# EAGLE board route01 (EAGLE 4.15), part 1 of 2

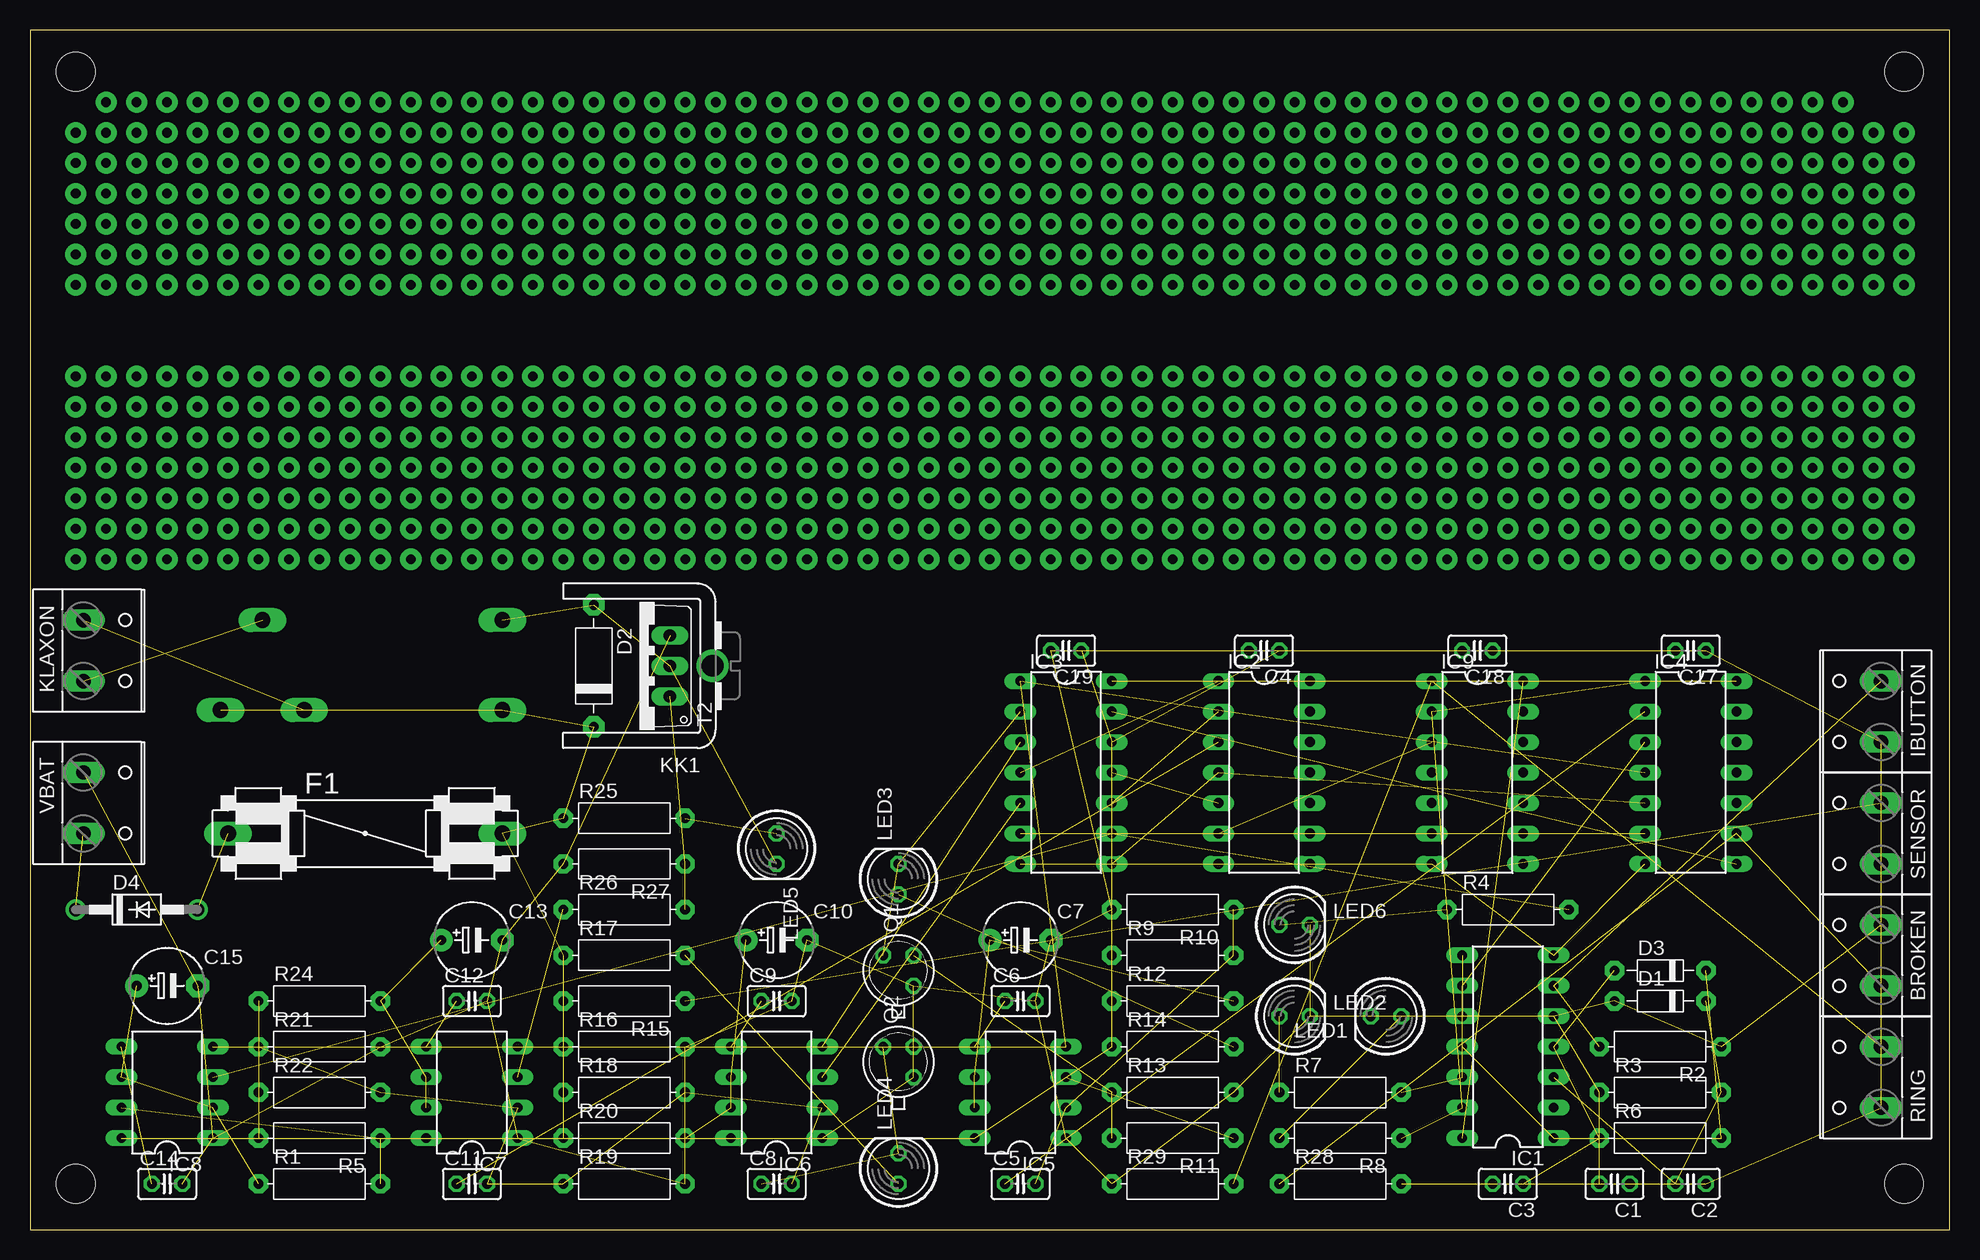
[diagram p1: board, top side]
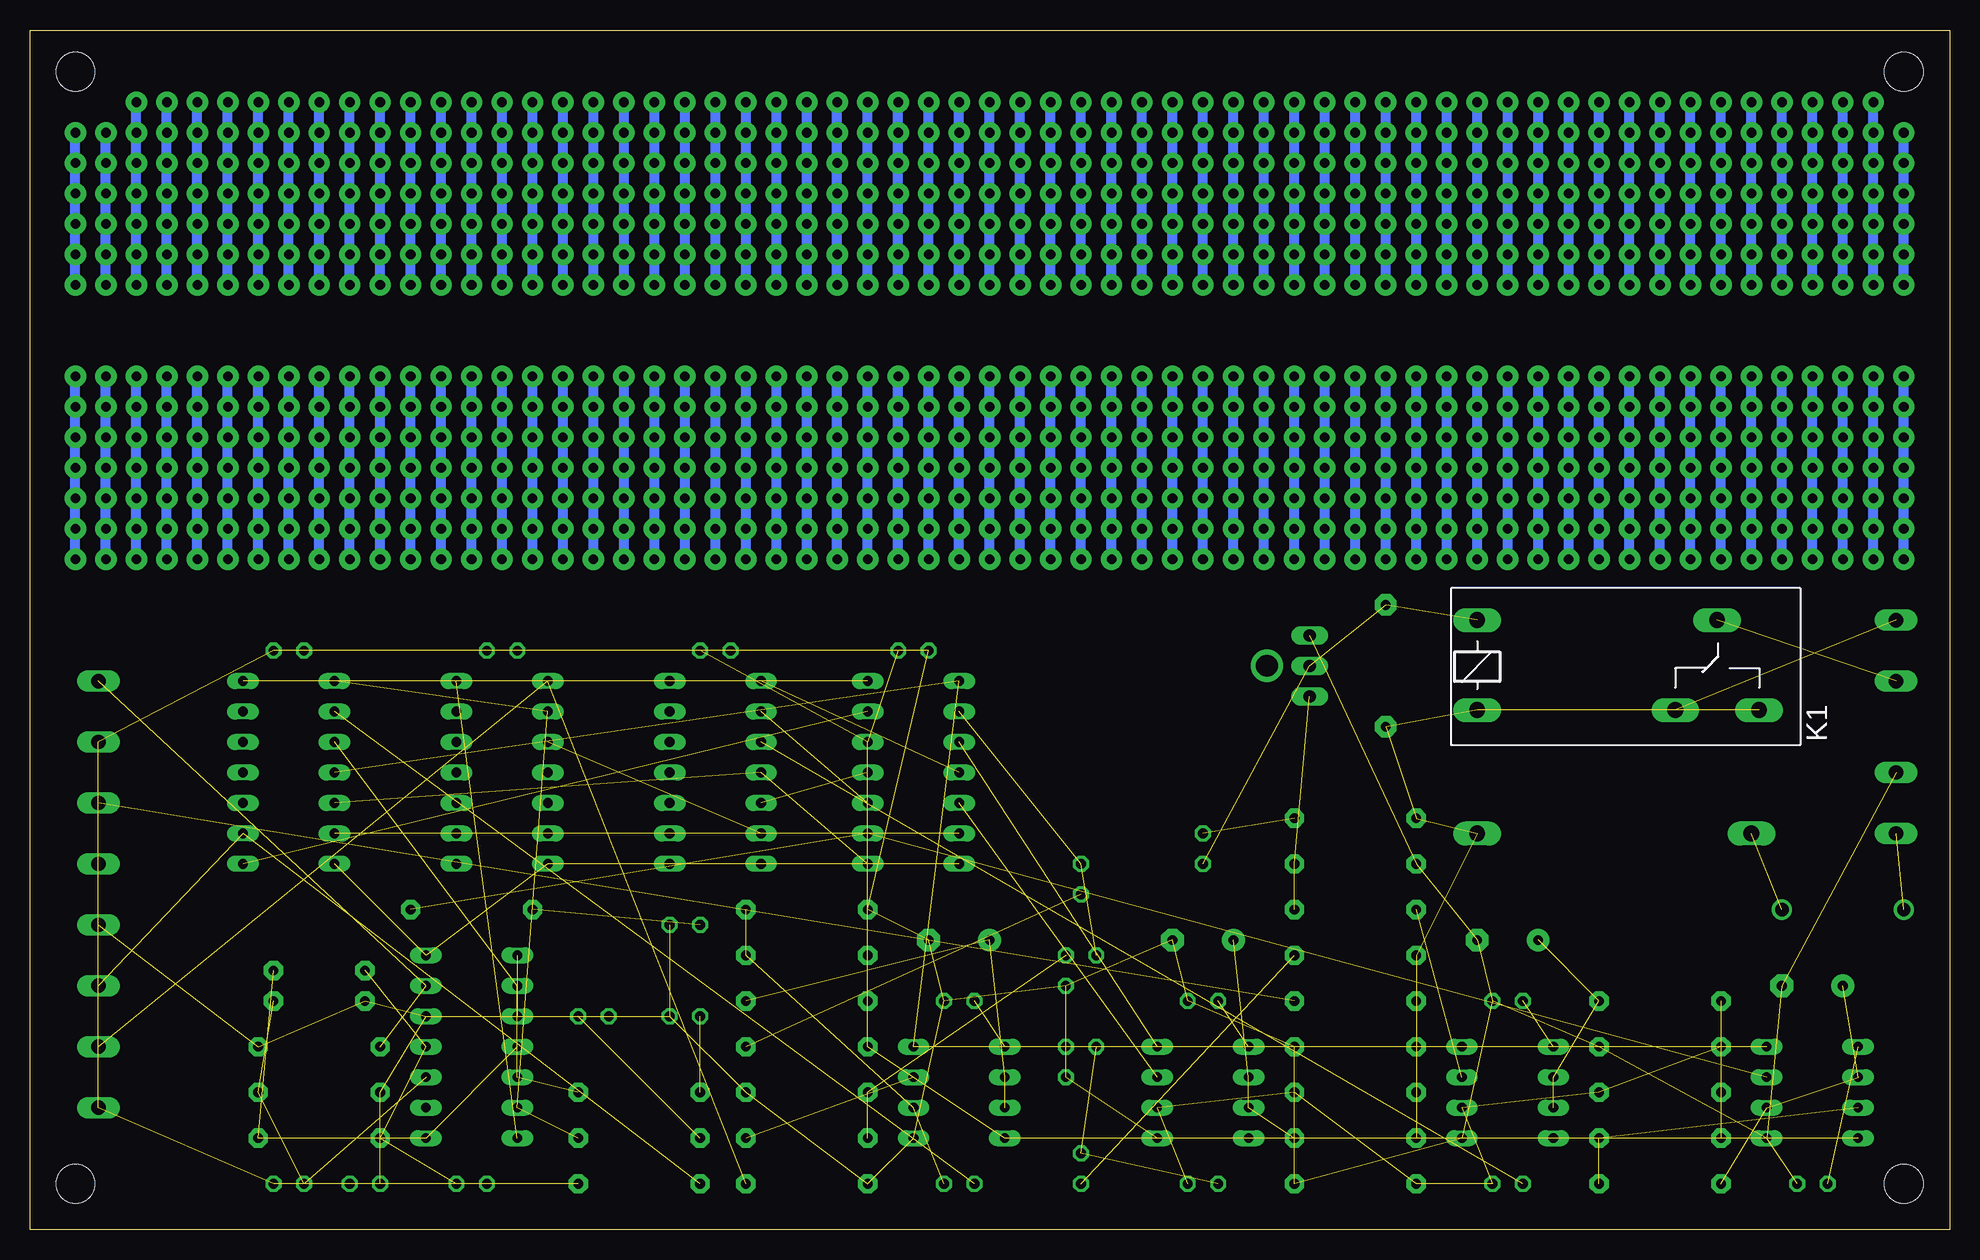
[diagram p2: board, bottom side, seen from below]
Size 160 x 100 mm. Coordinates in mm from the lower left corner, seen from the top.
Outline: 0,0 160,0 160,100 0,100 0,0
Copper layers (1*16): Top 0.035mm / dielectric 1.5mm / Bottom 0.035mm
Design rules "default": minimum track width 10mil, minimum drill 24mil, track to track 8mil, track to pad 8mil, pad to pad 8mil, via to via 8mil, smd to smd 8mil, copper to edge 40mil, drill to drill 8mil, minimum pad ring 10mil, minimum via ring 8mil, stop-mask expansion 4mil, vias tented up to drill 0mil, thermal gap 10mil
Holes 3.2 mm at 156.21,3.81 156.21,96.52 3.81,96.52 3.81,3.81

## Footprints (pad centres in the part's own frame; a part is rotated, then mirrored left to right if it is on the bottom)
W237-132 = drill 1.194 long: 1 -2.54,-0.635; 2 2.54,-0.635
C025-025X050 = drill 0.813 octagon: 1 -1.27,0; 2 1.27,0
E5-6 = drill 0.813 pad 1.905 round: + -2.54,0 | drill 0.813 pad 1.905 octagon: - 2.54,0
D-7,5 = drill 0.813 pad 1.6 octagon: 1 -3.81,0; 2 3.81,0
D-10 = drill 0.813 pad 1.778 octagon: 1 -5.08,0; 2 5.08,0
DO41-10 = drill 1.118 round: A 5.08,0; C -5.08,0
FUSE = drill 1.321 long: 1 -11.43,0; 2 11.43,0
DIL14 = drill 0.813 long: 1 -7.62,-3.81; 2 -5.08,-3.81; 3 -2.54,-3.81; 4 0,-3.81; 5 2.54,-3.81; 6 5.08,-3.81; 7 7.62,-3.81; 8 7.62,3.81; 9 5.08,3.81; 10 2.54,3.81; 11 0,3.81; 12 -2.54,3.81; 13 -5.08,3.81; 14 -7.62,3.81
DIL08 = drill 0.813 long: 1 -3.81,-3.81; 2 -1.27,-3.81; 3 1.27,-3.81; 4 3.81,-3.81; 5 3.81,3.81; 6 1.27,3.81; 7 -1.27,3.81; 8 -3.81,3.81
G2R = drill 1.321 long: 1 -2.54,-3.683; 2 -2.54,3.81; O 13.97,-3.683; P 17.45,3.81; S 20.955,-3.683
D01PA = drill 1.803 pad 2.54 round: B 0,-1.016
LED5MM = drill 0.813 octagon: A -1.27,0; K 1.27,0
TO18A = drill 0.813 octagon: B 1.27,-1.27; C 1.27,1.27; E -1.27,-1.27
R-10 = drill 0.813 pad 1.6 octagon: 1 -5.08,0; 2 5.08,0
TO220V = drill 1.016 long: 1 -2.54,-2.54; 2 0,-2.54; 3 2.54,-2.54

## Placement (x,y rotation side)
BROKEN  [W237-132]  153.67,22.86 90 top
C1  [C025-025X050]  132.08,3.81 180 top
C2  [C025-025X050]  138.43,3.81 180 top
C3  [C025-025X050]  123.19,3.81 180 top
C4  [C025-025X050]  102.87,48.26 180 top
C5  [C025-025X050]  82.55,3.81 0 top
C6  [C025-025X050]  82.55,19.05 0 top
C7  [E5-6]  82.55,24.13 0 top
C8  [C025-025X050]  62.23,3.81 0 top
C9  [C025-025X050]  62.23,19.05 0 top
C10  [E5-6]  62.23,24.13 0 top
C11  [C025-025X050]  36.83,3.81 0 top
C12  [C025-025X050]  36.83,19.05 0 top
C13  [E5-6]  36.83,24.13 0 top
C14  [C025-025X050]  11.43,3.81 0 top
C15  [E5-6]  11.43,20.32 0 top
C17  [C025-025X050]  138.43,48.26 180 top
C18  [C025-025X050]  120.65,48.26 180 top
C19  [C025-025X050]  86.36,48.26 180 top
D1  [D-7,5]  135.89,19.05 0 top
D2  [D-10]  46.99,46.99 270 top
D3  [D-7,5]  135.89,21.59 0 top
D4  1N4004  [DO41-10]  8.89,26.67 0 top
F1  [FUSE]  27.94,33.02 0 top
IBUTTON  [W237-132]  153.67,43.18 90 top
IC1  4013N  [DIL14]  123.19,15.24 90 top
IC2  4071N  [DIL14]  102.87,38.1 270 top
IC3  4081N  [DIL14]  86.36,38.1 270 top
IC4  4069N  [DIL14]  138.43,38.1 270 top
IC5  NE555N  [DIL08]  82.55,11.43 90 top
IC6  NE555N  [DIL08]  62.23,11.43 90 top
IC7  NE555N  [DIL08]  36.83,11.43 90 top
IC8  NE555N  [DIL08]  11.43,11.43 90 top
IC9  4081N  [DIL14]  120.65,38.1 270 top
K1  G2R  [G2R]  36.83,46.99 0 bottom
KK1  D01PA  [D01PA]  55.88,46.99 90 top
KLAXON  [W237-132]  5.08,48.26 270 top
LED1  [LED5MM]  113.03,17.78 180 top
LED2  [LED5MM]  105.41,17.78 0 top
LED3  [LED5MM]  72.39,29.21 90 top
LED4  [LED5MM]  72.39,5.08 90 top
LED5  [LED5MM]  62.23,31.75 270 top
LED6  [LED5MM]  105.41,25.4 0 top
Q1  2N2222  [TO18A]  72.39,21.59 90 top
Q2  2N2222  [TO18A]  72.39,13.97 90 top
R1  [R-10]  24.13,3.81 0 top
R2  [R-10]  135.89,15.24 180 top
R3  [R-10]  135.89,11.43 0 top
R4  [R-10]  123.19,26.67 0 top
R5  [R-10]  24.13,7.62 180 top
R6  [R-10]  135.89,7.62 0 top
R7  [R-10]  109.22,11.43 0 top
R8  [R-10]  109.22,7.62 180 top
R9  [R-10]  95.25,22.86 0 top
R10  [R-10]  95.25,26.67 180 top
R11  [R-10]  95.25,7.62 180 top
R12  [R-10]  95.25,19.05 0 top
R13  [R-10]  95.25,11.43 0 top
R14  [R-10]  95.25,15.24 0 top
R15  [R-10]  49.53,19.05 180 top
R16  [R-10]  49.53,15.24 0 top
R17  [R-10]  49.53,22.86 0 top
R18  [R-10]  49.53,11.43 0 top
R19  [R-10]  49.53,3.81 0 top
R20  [R-10]  49.53,7.62 0 top
R21  [R-10]  24.13,15.24 0 top
R22  [R-10]  24.13,11.43 0 top
R24  [R-10]  24.13,19.05 0 top
R25  [R-10]  49.53,34.29 0 top
R26  [R-10]  49.53,26.67 0 top
R27  [R-10]  49.53,30.48 180 top
R28  [R-10]  109.22,3.81 0 top
R29  [R-10]  95.25,3.81 0 top
RING  [W237-132]  153.67,12.7 90 top
SENSOR  [W237-132]  153.67,33.02 90 top
T2  [TO220V]  50.8,46.99 90 top
VBAT  [W237-132]  5.08,35.56 270 top

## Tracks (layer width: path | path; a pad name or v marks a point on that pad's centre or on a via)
ACTION  (1 unrouted)
ALERTE  (2 unrouted)
ARRACHEMENT  (2 unrouted)
BP_URGENCE  (2 unrouted)
CDE  (1 unrouted)
CLEAR  (1 unrouted)
GND  (38 unrouted)
INHIBE  (2 unrouted)
N$1  (3 unrouted)
N$2  (3 unrouted)
N$3  (1 unrouted)
N$4  (1 unrouted)
N$5  (1 unrouted)
N$6  (2 unrouted)
N$7  (3 unrouted)
N$8  (1 unrouted)
N$9  (3 unrouted)
N$10  (2 unrouted)
N$11  (1 unrouted)
N$12  (2 unrouted)
N$13  (2 unrouted)
N$14  (3 unrouted)
N$15  (1 unrouted)
N$16  (1 unrouted)
N$17  (1 unrouted)
N$18  (7 unrouted)
N$19  (1 unrouted)
N$20  (1 unrouted)
N$21  (2 unrouted)
N$22  (1 unrouted)
N$23  (3 unrouted)
N$24  (3 unrouted)
N$25  (1 unrouted)
N$26  (1 unrouted)
N$27  (1 unrouted)
N$28  (3 unrouted)
N$29  (1 unrouted)
N$30  (1 unrouted)
N$31  (2 unrouted)
N$32  (1 unrouted)
N$33  (1 unrouted)
N$34  (3 unrouted)
N$35  (1 unrouted)
N$36  (1 unrouted)
N$37  (1 unrouted)
N$38  (1 unrouted)
N$44  (via drill 0.8 pad 1.78)
  other vias: 92.71,81.28
N$45  (via drill 0.8 pad 1.78)
  other vias: 90.17,83.82
N$46  (via drill 0.8 pad 1.78)
  other vias: 92.71,78.74
N$47  (via drill 0.8 pad 1.78)
  other vias: 113.03,71.12
N$48  (via drill 0.8 pad 1.78)
  other vias: 113.03,68.58
N$49  (via drill 0.8 pad 1.78)
  other vias: 92.71,71.12
N$50  (via drill 0.8 pad 1.78)
  other vias: 92.71,68.58
N$51  (via drill 0.8 pad 1.78)
  other vias: 92.71,66.04
N$52  (via drill 0.8 pad 1.78)
  other vias: 92.71,63.5
N$53  (via drill 0.8 pad 1.78)
  other vias: 92.71,60.96
N$54  (via drill 0.8 pad 1.78)
  other vias: 92.71,58.42
N$55  (via drill 0.8 pad 1.78)
  other vias: 92.71,55.88
N$56  (via drill 0.8 pad 1.78)
  other vias: 92.71,83.82
N$57  (via drill 0.8 pad 1.78)
  other vias: 95.25,83.82
N$58  (via drill 0.8 pad 1.78)
  other vias: 95.25,81.28
N$59  (via drill 0.8 pad 1.78)
  other vias: 95.25,78.74
N$60  (via drill 0.8 pad 1.78)
  other vias: 97.79,83.82
N$61  (via drill 0.8 pad 1.78)
  other vias: 100.33,83.82
N$62  (via drill 0.8 pad 1.78)
  other vias: 100.33,81.28
N$63  (via drill 0.8 pad 1.78)
  other vias: 100.33,78.74
N$64  (via drill 0.8 pad 1.78)
  other vias: 113.03,66.04
N$65  (via drill 0.8 pad 1.78)
  other vias: 113.03,63.5
N$66  (via drill 0.8 pad 1.78)
  other vias: 100.33,71.12
N$67  (via drill 0.8 pad 1.78)
  other vias: 100.33,68.58
N$68  (via drill 0.8 pad 1.78)
  other vias: 97.79,81.28
N$69  (via drill 0.8 pad 1.78)
  other vias: 97.79,78.74
N$70  (via drill 0.8 pad 1.78)
  other vias: 115.57,63.5
N$71  (via drill 0.8 pad 1.78)
  other vias: 102.87,83.82
N$72  (via drill 0.8 pad 1.78)
  other vias: 105.41,83.82
N$73  (via drill 0.8 pad 1.78)
  other vias: 107.95,83.82
N$74  (via drill 0.8 pad 1.78)
  other vias: 110.49,83.82
N$75  (via drill 0.8 pad 1.78)
  other vias: 113.03,83.82
N$76  (via drill 0.8 pad 1.78)
  other vias: 115.57,83.82
N$77  (via drill 0.8 pad 1.78)
  other vias: 118.11,83.82
N$78  (via drill 0.8 pad 1.78)
  other vias: 120.65,83.82
N$79  (via drill 0.8 pad 1.78)
  other vias: 123.19,83.82
N$80  (via drill 0.8 pad 1.78)
  other vias: 125.73,83.82
N$81  (via drill 0.8 pad 1.78)
  other vias: 102.87,81.28
N$82  (via drill 0.8 pad 1.78)
  other vias: 105.41,81.28
N$83  (via drill 0.8 pad 1.78)
  other vias: 105.41,78.74
N$84  (via drill 0.8 pad 1.78)
  other vias: 115.57,71.12
N$85  (via drill 0.8 pad 1.78)
  other vias: 102.87,78.74
N$86  (via drill 0.8 pad 1.78)
  other vias: 118.11,71.12
N$87  (via drill 0.8 pad 1.78)
  other vias: 120.65,71.12
N$88  (via drill 0.8 pad 1.78)
  other vias: 120.65,68.58
N$89  (via drill 0.8 pad 1.78)
  other vias: 105.41,71.12
N$90  (via drill 0.8 pad 1.78)
  other vias: 102.87,71.12
N$91  (via drill 0.8 pad 1.78)
  other vias: 102.87,68.58
N$92  (via drill 0.8 pad 1.78)
  other vias: 105.41,68.58
N$93  (via drill 0.8 pad 1.78)
  other vias: 105.41,66.04
N$94  (via drill 0.8 pad 1.78)
  other vias: 102.87,66.04
N$95  (via drill 0.8 pad 1.78)
  other vias: 100.33,66.04
N$96  (via drill 0.8 pad 1.78)
  other vias: 100.33,63.5
N$97  (via drill 0.8 pad 1.78)
  other vias: 100.33,60.96
N$98  (via drill 0.8 pad 1.78)
  other vias: 100.33,58.42
N$99  (via drill 0.8 pad 1.78)
  other vias: 95.25,55.88
N$100  (via drill 0.8 pad 1.78)
  other vias: 95.25,58.42
N$101  (via drill 0.8 pad 1.78)
  other vias: 95.25,60.96
N$102  (via drill 0.8 pad 1.78)
  other vias: 95.25,63.5
N$103  (via drill 0.8 pad 1.78)
  other vias: 95.25,66.04
N$104  (via drill 0.8 pad 1.78)
  other vias: 95.25,68.58
N$105  (via drill 0.8 pad 1.78)
  other vias: 95.25,71.12
N$106  (via drill 0.8 pad 1.78)
  other vias: 120.65,66.04
N$107  (via drill 0.8 pad 1.78)
  other vias: 118.11,68.58
N$108  (via drill 0.8 pad 1.78)
  other vias: 115.57,68.58
N$109  (via drill 0.8 pad 1.78)
  other vias: 97.79,71.12
N$110  (via drill 0.8 pad 1.78)
  other vias: 97.79,68.58
N$111  (via drill 0.8 pad 1.78)
  other vias: 97.79,66.04
N$112  (via drill 0.8 pad 1.78)
  other vias: 97.79,63.5
N$113  (via drill 0.8 pad 1.78)
  other vias: 97.79,60.96
N$114  (via drill 0.8 pad 1.78)
  other vias: 97.79,58.42
N$115  (via drill 0.8 pad 1.78)
  other vias: 97.79,55.88
N$116  (via drill 0.8 pad 1.78)
  other vias: 107.95,81.28
N$117  (via drill 0.8 pad 1.78)
  other vias: 107.95,78.74
N$118  (via drill 0.8 pad 1.78)
  other vias: 125.73,71.12
N$119  (via drill 0.8 pad 1.78)
  other vias: 125.73,68.58
N$120  (via drill 0.8 pad 1.78)
  other vias: 107.95,71.12
N$121  (via drill 0.8 pad 1.78)
  other vias: 107.95,68.58
N$122  (via drill 0.8 pad 1.78)
  other vias: 107.95,66.04
N$123  (via drill 0.8 pad 1.78)
  other vias: 107.95,63.5
N$124  (via drill 0.8 pad 1.78)
  other vias: 107.95,60.96
N$125  (via drill 0.8 pad 1.78)
  other vias: 107.95,58.42
N$126  (via drill 0.8 pad 1.78)
  other vias: 107.95,55.88
N$127  (via drill 0.8 pad 1.78)
  other vias: 105.41,55.88
N$128  (via drill 0.8 pad 1.78)
  other vias: 102.87,55.88
N$129  (via drill 0.8 pad 1.78)
  other vias: 105.41,58.42
N$130  (via drill 0.8 pad 1.78)
  other vias: 105.41,60.96
N$131  (via drill 0.8 pad 1.78)
  other vias: 105.41,63.5
N$132  (via drill 0.8 pad 1.78)
  other vias: 102.87,63.5
N$133  (via drill 0.8 pad 1.78)
  other vias: 102.87,60.96
N$134  (via drill 0.8 pad 1.78)
  other vias: 102.87,58.42
N$135  (via drill 0.8 pad 1.78)
  other vias: 110.49,55.88
N$136  (via drill 0.8 pad 1.78)
  other vias: 113.03,55.88
N$137  (via drill 0.8 pad 1.78)
  other vias: 115.57,55.88
N$138  (via drill 0.8 pad 1.78)
  other vias: 118.11,55.88
N$139  (via drill 0.8 pad 1.78)
  other vias: 120.65,55.88
N$140  (via drill 0.8 pad 1.78)
  other vias: 123.19,55.88
N$141  (via drill 0.8 pad 1.78)
  other vias: 125.73,55.88
N$142  (via drill 0.8 pad 1.78)
  other vias: 128.27,55.88
N$143  (via drill 0.8 pad 1.78)
  other vias: 130.81,55.88
N$144  (via drill 0.8 pad 1.78)
  other vias: 133.35,55.88
N$145  (via drill 0.8 pad 1.78)
  other vias: 135.89,55.88
N$146  (via drill 0.8 pad 1.78)
  other vias: 138.43,55.88
N$147  (via drill 0.8 pad 1.78)
  other vias: 140.97,55.88
N$148  (via drill 0.8 pad 1.78)
  other vias: 143.51,55.88
N$149  (via drill 0.8 pad 1.78)
  other vias: 146.05,55.88
N$150  (via drill 0.8 pad 1.78)
  other vias: 148.59,55.88
N$151  (via drill 0.8 pad 1.78)
  other vias: 151.13,55.88
N$152  (via drill 0.8 pad 1.78)
  other vias: 153.67,55.88
N$153  (via drill 0.8 pad 1.78)
  other vias: 156.21,55.88
N$154  (via drill 0.8 pad 1.78)
  other vias: 156.21,58.42
N$155  (via drill 0.8 pad 1.78)
  other vias: 153.67,58.42
N$156  (via drill 0.8 pad 1.78)
  other vias: 110.49,81.28
N$157  (via drill 0.8 pad 1.78)
  other vias: 110.49,58.42
N$158  (via drill 0.8 pad 1.78)
  other vias: 110.49,60.96
N$159  (via drill 0.8 pad 1.78)
  other vias: 110.49,63.5
N$160  (via drill 0.8 pad 1.78)
  other vias: 110.49,66.04
N$161  (via drill 0.8 pad 1.78)
  other vias: 110.49,68.58
N$162  (via drill 0.8 pad 1.78)
  other vias: 110.49,71.12
N$163  (via drill 0.8 pad 1.78)
  other vias: 125.73,66.04
N$164  (via drill 0.8 pad 1.78)
  other vias: 125.73,63.5
N$165  (via drill 0.8 pad 1.78)
  other vias: 110.49,78.74
N$166  (via drill 0.8 pad 1.78)
  other vias: 125.73,78.74
N$167  (via drill 0.8 pad 1.78)
  other vias: 64.77,55.88
N$168  (via drill 0.8 pad 1.78)
  other vias: 62.23,55.88
N$169  (via drill 0.8 pad 1.78)
  other vias: 123.19,71.12
N$170  (via drill 0.8 pad 1.78)
  other vias: 123.19,68.58
N$171  (via drill 0.8 pad 1.78)
  other vias: 123.19,66.04
N$172  (via drill 0.8 pad 1.78)
  other vias: 123.19,63.5
N$173  (via drill 0.8 pad 1.78)
  other vias: 123.19,58.42
N$174  (via drill 0.8 pad 1.78)
  other vias: 120.65,58.42
N$175  (via drill 0.8 pad 1.78)
  other vias: 128.27,58.42
N$176  (via drill 0.8 pad 1.78)
  other vias: 128.27,60.96
N$177  (via drill 0.8 pad 1.78)
  other vias: 125.73,58.42
N$178  (via drill 0.8 pad 1.78)
  other vias: 125.73,60.96
N$179  (via drill 0.8 pad 1.78)
  other vias: 123.19,60.96
N$180  (via drill 0.8 pad 1.78)
  other vias: 113.03,60.96
N$181  (via drill 0.8 pad 1.78)
  other vias: 115.57,60.96
N$182  (via drill 0.8 pad 1.78)
  other vias: 118.11,60.96
N$183  (via drill 0.8 pad 1.78)
  other vias: 120.65,60.96
N$184  (via drill 0.8 pad 1.78)
  other vias: 120.65,63.5
N$185  (via drill 0.8 pad 1.78)
  other vias: 118.11,63.5
N$186  (via drill 0.8 pad 1.78)
  other vias: 133.35,60.96
N$187  (via drill 0.8 pad 1.78)
  other vias: 118.11,66.04
N$188  (via drill 0.8 pad 1.78)
  other vias: 115.57,66.04
N$189  (via drill 0.8 pad 1.78)
  other vias: 135.89,60.96
N$190  (via drill 0.8 pad 1.78)
  other vias: 135.89,63.5
N$191  (via drill 0.8 pad 1.78)
  other vias: 133.35,63.5
N$192  (via drill 0.8 pad 1.78)
  other vias: 130.81,63.5
N$193  (via drill 0.8 pad 1.78)
  other vias: 128.27,63.5
N$194  (via drill 0.8 pad 1.78)
  other vias: 115.57,81.28
N$195  (via drill 0.8 pad 1.78)
  other vias: 100.33,55.88
N$196  (via drill 0.8 pad 1.78)
  other vias: 113.03,58.42
N$197  (via drill 0.8 pad 1.78)
  other vias: 118.11,58.42
N$198  (via drill 0.8 pad 1.78)
  other vias: 115.57,58.42
N$199  (via drill 0.8 pad 1.78)
  other vias: 135.89,58.42
N$200  (via drill 0.8 pad 1.78)
  other vias: 133.35,58.42
N$201  (via drill 0.8 pad 1.78)
  other vias: 130.81,58.42
N$202  (via drill 0.8 pad 1.78)
  other vias: 130.81,60.96
N$203  (via drill 0.8 pad 1.78)
  other vias: 128.27,66.04
N$204  (via drill 0.8 pad 1.78)
  other vias: 128.27,68.58
N$205  (via drill 0.8 pad 1.78)
  other vias: 128.27,71.12
N$206  (via drill 0.8 pad 1.78)
  other vias: 130.81,71.12
N$207  (via drill 0.8 pad 1.78)
  other vias: 130.81,68.58
N$208  (via drill 0.8 pad 1.78)
  other vias: 130.81,66.04
N$209  (via drill 0.8 pad 1.78)
  other vias: 133.35,66.04
N$210  (via drill 0.8 pad 1.78)
  other vias: 135.89,66.04
N$211  (via drill 0.8 pad 1.78)
  other vias: 135.89,68.58
N$212  (via drill 0.8 pad 1.78)
  other vias: 133.35,68.58
N$213  (via drill 0.8 pad 1.78)
  other vias: 133.35,71.12
N$214  (via drill 0.8 pad 1.78)
  other vias: 135.89,71.12
N$215  (via drill 0.8 pad 1.78)
  other vias: 146.05,58.42
N$216  (via drill 0.8 pad 1.78)
  other vias: 143.51,58.42
N$217  (via drill 0.8 pad 1.78)
  other vias: 140.97,58.42
N$218  (via drill 0.8 pad 1.78)
  other vias: 138.43,58.42
N$219  (via drill 0.8 pad 1.78)
  other vias: 138.43,60.96
N$220  (via drill 0.8 pad 1.78)
  other vias: 138.43,63.5
N$221  (via drill 0.8 pad 1.78)
  other vias: 138.43,66.04
N$222  (via drill 0.8 pad 1.78)
  other vias: 138.43,68.58
N$223  (via drill 0.8 pad 1.78)
  other vias: 138.43,71.12
N$224  (via drill 0.8 pad 1.78)
  other vias: 146.05,60.96
N$225  (via drill 0.8 pad 1.78)
  other vias: 146.05,63.5
N$226  (via drill 0.8 pad 1.78)
  other vias: 146.05,66.04
N$227  (via drill 0.8 pad 1.78)
  other vias: 146.05,68.58
N$228  (via drill 0.8 pad 1.78)
  other vias: 146.05,71.12
N$229  (via drill 0.8 pad 1.78)
  other vias: 143.51,71.12
N$230  (via drill 0.8 pad 1.78)
  other vias: 140.97,71.12
N$231  (via drill 0.8 pad 1.78)
  other vias: 140.97,68.58
N$232  (via drill 0.8 pad 1.78)
  other vias: 143.51,68.58
N$233  (via drill 0.8 pad 1.78)
  other vias: 143.51,66.04
N$234  (via drill 0.8 pad 1.78)
  other vias: 143.51,63.5
N$235  (via drill 0.8 pad 1.78)
  other vias: 143.51,60.96
N$236  (via drill 0.8 pad 1.78)
  other vias: 140.97,60.96
N$237  (via drill 0.8 pad 1.78)
  other vias: 140.97,63.5
N$238  (via drill 0.8 pad 1.78)
  other vias: 140.97,66.04
N$239  (via drill 0.8 pad 1.78)
  other vias: 148.59,58.42
N$240  (via drill 0.8 pad 1.78)
  other vias: 148.59,60.96
N$241  (via drill 0.8 pad 1.78)
  other vias: 151.13,58.42
N$242  (via drill 0.8 pad 1.78)
  other vias: 148.59,63.5
N$243  (via drill 0.8 pad 1.78)
  other vias: 148.59,66.04
N$244  (via drill 0.8 pad 1.78)
  other vias: 148.59,68.58
N$245  (via drill 0.8 pad 1.78)
  other vias: 148.59,71.12
N$246  (via drill 0.8 pad 1.78)
  other vias: 151.13,71.12
N$247  (via drill 0.8 pad 1.78)
  other vias: 151.13,68.58
N$248  (via drill 0.8 pad 1.78)
  other vias: 151.13,66.04
N$249  (via drill 0.8 pad 1.78)
  other vias: 151.13,63.5
N$250  (via drill 0.8 pad 1.78)
  other vias: 151.13,60.96
N$251  (via drill 0.8 pad 1.78)
  other vias: 153.67,60.96
N$252  (via drill 0.8 pad 1.78)
  other vias: 156.21,60.96
N$253  (via drill 0.8 pad 1.78)
  other vias: 156.21,63.5
N$254  (via drill 0.8 pad 1.78)
  other vias: 153.67,63.5
N$255  (via drill 0.8 pad 1.78)
  other vias: 156.21,66.04
N$256  (via drill 0.8 pad 1.78)
  other vias: 153.67,66.04
N$257  (via drill 0.8 pad 1.78)
  other vias: 153.67,68.58
N$258  (via drill 0.8 pad 1.78)
  other vias: 156.21,68.58
N$259  (via drill 0.8 pad 1.78)
  other vias: 156.21,71.12
N$260  (via drill 0.8 pad 1.78)
  other vias: 153.67,71.12
N$261  (via drill 0.8 pad 1.78)
  other vias: 90.17,55.88
N$262  (via drill 0.8 pad 1.78)
  other vias: 87.63,55.88
N$263  (via drill 0.8 pad 1.78)
  other vias: 85.09,55.88
N$264  (via drill 0.8 pad 1.78)
  other vias: 82.55,55.88
N$265  (via drill 0.8 pad 1.78)
  other vias: 80.01,55.88
N$266  (via drill 0.8 pad 1.78)
  other vias: 77.47,55.88
N$267  (via drill 0.8 pad 1.78)
  other vias: 74.93,55.88
N$268  (via drill 0.8 pad 1.78)
  other vias: 72.39,55.88
N$269  (via drill 0.8 pad 1.78)
  other vias: 69.85,55.88
N$270  (via drill 0.8 pad 1.78)
  other vias: 67.31,55.88
N$271  (via drill 0.8 pad 1.78)
  other vias: 90.17,58.42
N$272  (via drill 0.8 pad 1.78)
  other vias: 80.01,66.04
N$273  (via drill 0.8 pad 1.78)
  other vias: 80.01,60.96
N$274  (via drill 0.8 pad 1.78)
  other vias: 80.01,58.42
N$275  (via drill 0.8 pad 1.78)
  other vias: 82.55,58.42
N$276  (via drill 0.8 pad 1.78)
  other vias: 82.55,60.96
N$277  (via drill 0.8 pad 1.78)
  other vias: 82.55,71.12
N$278  (via drill 0.8 pad 1.78)
  other vias: 82.55,68.58
N$279  (via drill 0.8 pad 1.78)
  other vias: 82.55,66.04
N$280  (via drill 0.8 pad 1.78)
  other vias: 82.55,63.5
N$281  (via drill 0.8 pad 1.78)
  other vias: 72.39,58.42
N$282  (via drill 0.8 pad 1.78)
  other vias: 72.39,60.96
N$283  (via drill 0.8 pad 1.78)
  other vias: 72.39,63.5
N$284  (via drill 0.8 pad 1.78)
  other vias: 72.39,66.04
N$285  (via drill 0.8 pad 1.78)
  other vias: 72.39,68.58
N$286  (via drill 0.8 pad 1.78)
  other vias: 72.39,71.12
N$287  (via drill 0.8 pad 1.78)
  other vias: 67.31,58.42
N$288  (via drill 0.8 pad 1.78)
  other vias: 67.31,60.96
N$289  (via drill 0.8 pad 1.78)
  other vias: 67.31,63.5
N$290  (via drill 0.8 pad 1.78)
  other vias: 67.31,71.12
N$291  (via drill 0.8 pad 1.78)
  other vias: 67.31,68.58
N$292  (via drill 0.8 pad 1.78)
  other vias: 67.31,66.04
N$293  (via drill 0.8 pad 1.78)
  other vias: 69.85,58.42
N$294  (via drill 0.8 pad 1.78)
  other vias: 69.85,60.96
N$295  (via drill 0.8 pad 1.78)
  other vias: 69.85,63.5
N$296  (via drill 0.8 pad 1.78)
  other vias: 69.85,66.04
N$297  (via drill 0.8 pad 1.78)
  other vias: 69.85,68.58
N$298  (via drill 0.8 pad 1.78)
  other vias: 69.85,71.12
N$299  (via drill 0.8 pad 1.78)
  other vias: 74.93,71.12
N$300  (via drill 0.8 pad 1.78)
  other vias: 74.93,68.58
N$301  (via drill 0.8 pad 1.78)
  other vias: 74.93,66.04
N$302  (via drill 0.8 pad 1.78)
  other vias: 74.93,63.5
N$303  (via drill 0.8 pad 1.78)
  other vias: 74.93,60.96
N$304  (via drill 0.8 pad 1.78)
  other vias: 74.93,58.42
N$305  (via drill 0.8 pad 1.78)
  other vias: 77.47,58.42
N$306  (via drill 0.8 pad 1.78)
  other vias: 77.47,60.96
N$307  (via drill 0.8 pad 1.78)
  other vias: 77.47,63.5
N$308  (via drill 0.8 pad 1.78)
  other vias: 77.47,66.04
N$309  (via drill 0.8 pad 1.78)
  other vias: 77.47,68.58
N$310  (via drill 0.8 pad 1.78)
  other vias: 77.47,71.12
N$311  (via drill 0.8 pad 1.78)
  other vias: 80.01,71.12
N$312  (via drill 0.8 pad 1.78)
  other vias: 80.01,68.58
N$313  (via drill 0.8 pad 1.78)
  other vias: 90.17,71.12
N$314  (via drill 0.8 pad 1.78)
  other vias: 87.63,71.12
N$315  (via drill 0.8 pad 1.78)
  other vias: 85.09,71.12
N$316  (via drill 0.8 pad 1.78)
  other vias: 85.09,68.58
N$317  (via drill 0.8 pad 1.78)
  other vias: 85.09,66.04
N$318  (via drill 0.8 pad 1.78)
  other vias: 85.09,63.5
N$319  (via drill 0.8 pad 1.78)
  other vias: 85.09,60.96
N$320  (via drill 0.8 pad 1.78)
  other vias: 87.63,58.42
N$321  (via drill 0.8 pad 1.78)
  other vias: 85.09,58.42
N$322  (via drill 0.8 pad 1.78)
  other vias: 87.63,60.96
N$323  (via drill 0.8 pad 1.78)
  other vias: 90.17,60.96
N$324  (via drill 0.8 pad 1.78)
  other vias: 90.17,63.5
N$325  (via drill 0.8 pad 1.78)
  other vias: 87.63,63.5
N$326  (via drill 0.8 pad 1.78)
  other vias: 87.63,66.04
N$327  (via drill 0.8 pad 1.78)
  other vias: 90.17,66.04
N$328  (via drill 0.8 pad 1.78)
  other vias: 90.17,68.58
N$329  (via drill 0.8 pad 1.78)
  other vias: 87.63,68.58
N$330  (via drill 0.8 pad 1.78)
  other vias: 80.01,63.5
N$331  (via drill 0.8 pad 1.78)
  other vias: 90.17,78.74
N$332  (via drill 0.8 pad 1.78)
  other vias: 87.63,78.74
N$333  (via drill 0.8 pad 1.78)
  other vias: 85.09,78.74
N$334  (via drill 0.8 pad 1.78)
  other vias: 82.55,78.74
N$335  (via drill 0.8 pad 1.78)
  other vias: 80.01,78.74
N$336  (via drill 0.8 pad 1.78)
  other vias: 77.47,78.74
N$337  (via drill 0.8 pad 1.78)
  other vias: 74.93,78.74
N$338  (via drill 0.8 pad 1.78)
  other vias: 72.39,78.74
N$339  (via drill 0.8 pad 1.78)
  other vias: 69.85,78.74
N$340  (via drill 0.8 pad 1.78)
  other vias: 67.31,78.74
N$341  (via drill 0.8 pad 1.78)
  other vias: 67.31,81.28
N$342  (via drill 0.8 pad 1.78)
  other vias: 67.31,83.82
N$343  (via drill 0.8 pad 1.78)
  other vias: 67.31,86.36
N$344  (via drill 0.8 pad 1.78)
  other vias: 67.31,88.9
N$345  (via drill 0.8 pad 1.78)
  other vias: 67.31,91.44
N$346  (via drill 0.8 pad 1.78)
  other vias: 67.31,93.98
N$347  (via drill 0.8 pad 1.78)
  other vias: 69.85,81.28
N$348  (via drill 0.8 pad 1.78)
  other vias: 69.85,83.82
N$349  (via drill 0.8 pad 1.78)
  other vias: 69.85,86.36
N$350  (via drill 0.8 pad 1.78)
  other vias: 69.85,88.9
N$351  (via drill 0.8 pad 1.78)
  other vias: 69.85,91.44
N$352  (via drill 0.8 pad 1.78)
  other vias: 69.85,93.98
N$353  (via drill 0.8 pad 1.78)
  other vias: 72.39,81.28
N$354  (via drill 0.8 pad 1.78)
  other vias: 72.39,83.82
N$355  (via drill 0.8 pad 1.78)
  other vias: 72.39,86.36
N$356  (via drill 0.8 pad 1.78)
  other vias: 72.39,88.9
N$357  (via drill 0.8 pad 1.78)
  other vias: 72.39,91.44
N$358  (via drill 0.8 pad 1.78)
  other vias: 72.39,93.98
N$359  (via drill 0.8 pad 1.78)
  other vias: 80.01,81.28
N$360  (via drill 0.8 pad 1.78)
  other vias: 77.47,81.28
N$361  (via drill 0.8 pad 1.78)
  other vias: 74.93,81.28
N$362  (via drill 0.8 pad 1.78)
  other vias: 80.01,83.82
N$363  (via drill 0.8 pad 1.78)
  other vias: 80.01,86.36
N$364  (via drill 0.8 pad 1.78)
  other vias: 80.01,88.9
N$365  (via drill 0.8 pad 1.78)
  other vias: 80.01,91.44
N$366  (via drill 0.8 pad 1.78)
  other vias: 80.01,93.98
N$367  (via drill 0.8 pad 1.78)
  other vias: 77.47,93.98
N$368  (via drill 0.8 pad 1.78)
  other vias: 77.47,91.44
N$369  (via drill 0.8 pad 1.78)
  other vias: 74.93,93.98
N$370  (via drill 0.8 pad 1.78)
  other vias: 74.93,91.44
N$371  (via drill 0.8 pad 1.78)
  other vias: 74.93,88.9
N$372  (via drill 0.8 pad 1.78)
  other vias: 74.93,86.36
N$373  (via drill 0.8 pad 1.78)
  other vias: 74.93,83.82
N$374  (via drill 0.8 pad 1.78)
  other vias: 77.47,83.82
N$375  (via drill 0.8 pad 1.78)
  other vias: 77.47,86.36
N$376  (via drill 0.8 pad 1.78)
  other vias: 77.47,88.9
N$377  (via drill 0.8 pad 1.78)
  other vias: 82.55,81.28
N$378  (via drill 0.8 pad 1.78)
  other vias: 82.55,83.82
N$379  (via drill 0.8 pad 1.78)
  other vias: 82.55,86.36
N$380  (via drill 0.8 pad 1.78)
  other vias: 82.55,88.9
N$381  (via drill 0.8 pad 1.78)
  other vias: 82.55,91.44
N$382  (via drill 0.8 pad 1.78)
  other vias: 82.55,93.98
N$383  (via drill 0.8 pad 1.78)
  other vias: 128.27,78.74
N$384  (via drill 0.8 pad 1.78)
  other vias: 130.81,78.74
N$385  (via drill 0.8 pad 1.78)
  other vias: 133.35,78.74
N$386  (via drill 0.8 pad 1.78)
  other vias: 135.89,78.74
N$387  (via drill 0.8 pad 1.78)
  other vias: 135.89,81.28
N$388  (via drill 0.8 pad 1.78)
  other vias: 135.89,83.82
N$389  (via drill 0.8 pad 1.78)
  other vias: 128.27,83.82
N$390  (via drill 0.8 pad 1.78)
  other vias: 130.81,83.82
N$391  (via drill 0.8 pad 1.78)
  other vias: 133.35,83.82
N$392  (via drill 0.8 pad 1.78)
  other vias: 133.35,81.28
N$393  (via drill 0.8 pad 1.78)
  other vias: 130.81,81.28
N$394  (via drill 0.8 pad 1.78)
  other vias: 128.27,81.28
N$395  (via drill 0.8 pad 1.78)
  other vias: 125.73,81.28
N$396  (via drill 0.8 pad 1.78)
  other vias: 123.19,81.28
N$397  (via drill 0.8 pad 1.78)
  other vias: 85.09,81.28
N$398  (via drill 0.8 pad 1.78)
  other vias: 118.11,81.28
N$399  (via drill 0.8 pad 1.78)
  other vias: 123.19,78.74
N$400  (via drill 0.8 pad 1.78)
  other vias: 120.65,78.74
N$401  (via drill 0.8 pad 1.78)
  other vias: 118.11,78.74
N$402  (via drill 0.8 pad 1.78)
  other vias: 115.57,78.74
N$403  (via drill 0.8 pad 1.78)
  other vias: 113.03,78.74
N$404  (via drill 0.8 pad 1.78)
  other vias: 113.03,81.28
N$405  (via drill 0.8 pad 1.78)
  other vias: 120.65,81.28
N$406  (via drill 0.8 pad 1.78)
  other vias: 92.71,86.36
N$407  (via drill 0.8 pad 1.78)
  other vias: 90.17,86.36
N$408  (via drill 0.8 pad 1.78)
  other vias: 87.63,86.36
N$409  (via drill 0.8 pad 1.78)
  other vias: 85.09,86.36
N$410  (via drill 0.8 pad 1.78)
  other vias: 85.09,83.82
N$411  (via drill 0.8 pad 1.78)
  other vias: 87.63,83.82
N$412  (via drill 0.8 pad 1.78)
  other vias: 87.63,81.28
N$413  (via drill 0.8 pad 1.78)
  other vias: 90.17,81.28
N$414  (via drill 0.8 pad 1.78)
  other vias: 135.89,86.36
N$415  (via drill 0.8 pad 1.78)
  other vias: 135.89,88.9
N$416  (via drill 0.8 pad 1.78)
  other vias: 135.89,91.44
N$417  (via drill 0.8 pad 1.78)
  other vias: 133.35,91.44
N$418  (via drill 0.8 pad 1.78)
  other vias: 133.35,88.9
N$419  (via drill 0.8 pad 1.78)
  other vias: 133.35,86.36
N$420  (via drill 0.8 pad 1.78)
  other vias: 130.81,86.36
N$421  (via drill 0.8 pad 1.78)
  other vias: 128.27,86.36
N$422  (via drill 0.8 pad 1.78)
  other vias: 125.73,86.36
N$423  (via drill 0.8 pad 1.78)
  other vias: 125.73,88.9
N$424  (via drill 0.8 pad 1.78)
  other vias: 128.27,88.9
N$425  (via drill 0.8 pad 1.78)
  other vias: 130.81,88.9
N$426  (via drill 0.8 pad 1.78)
  other vias: 130.81,91.44
N$427  (via drill 0.8 pad 1.78)
  other vias: 128.27,91.44
N$428  (via drill 0.8 pad 1.78)
  other vias: 125.73,91.44
N$429  (via drill 0.8 pad 1.78)
  other vias: 138.43,78.74
N$430  (via drill 0.8 pad 1.78)
  other vias: 156.21,78.74
N$431  (via drill 0.8 pad 1.78)
  other vias: 153.67,78.74
N$432  (via drill 0.8 pad 1.78)
  other vias: 156.21,91.44
N$433  (via drill 0.8 pad 1.78)
  other vias: 153.67,91.44
N$434  (via drill 0.8 pad 1.78)
  other vias: 151.13,91.44
N$435  (via drill 0.8 pad 1.78)
  other vias: 148.59,91.44
N$436  (via drill 0.8 pad 1.78)
  other vias: 146.05,91.44
N$437  (via drill 0.8 pad 1.78)
  other vias: 143.51,91.44
N$438  (via drill 0.8 pad 1.78)
  other vias: 140.97,91.44
N$439  (via drill 0.8 pad 1.78)
  other vias: 138.43,91.44
N$440  (via drill 0.8 pad 1.78)
  other vias: 138.43,88.9
N$441  (via drill 0.8 pad 1.78)
  other vias: 138.43,86.36
N$442  (via drill 0.8 pad 1.78)
  other vias: 138.43,83.82
N$443  (via drill 0.8 pad 1.78)
  other vias: 138.43,81.28
N$444  (via drill 0.8 pad 1.78)
  other vias: 140.97,78.74
N$445  (via drill 0.8 pad 1.78)
  other vias: 143.51,78.74
N$446  (via drill 0.8 pad 1.78)
  other vias: 146.05,78.74
N$447  (via drill 0.8 pad 1.78)
  other vias: 148.59,78.74
N$448  (via drill 0.8 pad 1.78)
  other vias: 151.13,78.74
N$449  (via drill 0.8 pad 1.78)
  other vias: 151.13,81.28
N$450  (via drill 0.8 pad 1.78)
  other vias: 148.59,81.28
N$451  (via drill 0.8 pad 1.78)
  other vias: 146.05,81.28
N$452  (via drill 0.8 pad 1.78)
  other vias: 143.51,81.28
N$453  (via drill 0.8 pad 1.78)
  other vias: 140.97,81.28
N$454  (via drill 0.8 pad 1.78)
  other vias: 140.97,83.82
N$455  (via drill 0.8 pad 1.78)
  other vias: 143.51,83.82
N$456  (via drill 0.8 pad 1.78)
  other vias: 146.05,83.82
N$457  (via drill 0.8 pad 1.78)
  other vias: 148.59,83.82
N$458  (via drill 0.8 pad 1.78)
  other vias: 151.13,83.82
N$459  (via drill 0.8 pad 1.78)
  other vias: 151.13,86.36
N$460  (via drill 0.8 pad 1.78)
  other vias: 151.13,88.9
N$461  (via drill 0.8 pad 1.78)
  other vias: 148.59,88.9
N$462  (via drill 0.8 pad 1.78)
  other vias: 148.59,86.36
N$463  (via drill 0.8 pad 1.78)
  other vias: 146.05,86.36
N$464  (via drill 0.8 pad 1.78)
  other vias: 146.05,88.9
N$465  (via drill 0.8 pad 1.78)
  other vias: 143.51,88.9
N$466  (via drill 0.8 pad 1.78)
  other vias: 140.97,88.9
N$467  (via drill 0.8 pad 1.78)
  other vias: 140.97,86.36
N$468  (via drill 0.8 pad 1.78)
  other vias: 143.51,86.36
N$469  (via drill 0.8 pad 1.78)
  other vias: 153.67,88.9
N$470  (via drill 0.8 pad 1.78)
  other vias: 153.67,86.36
N$471  (via drill 0.8 pad 1.78)
  other vias: 153.67,83.82
N$472  (via drill 0.8 pad 1.78)
  other vias: 153.67,81.28
N$473  (via drill 0.8 pad 1.78)
  other vias: 156.21,81.28
N$474  (via drill 0.8 pad 1.78)
  other vias: 156.21,83.82
N$475  (via drill 0.8 pad 1.78)
  other vias: 156.21,86.36
N$476  (via drill 0.8 pad 1.78)
  other vias: 156.21,88.9
N$477  (via drill 0.8 pad 1.78)
  other vias: 118.11,86.36
N$478  (via drill 0.8 pad 1.78)
  other vias: 118.11,88.9
N$479  (via drill 0.8 pad 1.78)
  other vias: 118.11,91.44
N$480  (via drill 0.8 pad 1.78)
  other vias: 120.65,86.36
N$481  (via drill 0.8 pad 1.78)
  other vias: 123.19,86.36
N$482  (via drill 0.8 pad 1.78)
  other vias: 123.19,88.9
N$483  (via drill 0.8 pad 1.78)
  other vias: 120.65,88.9
N$484  (via drill 0.8 pad 1.78)
  other vias: 120.65,91.44
N$485  (via drill 0.8 pad 1.78)
  other vias: 123.19,91.44
N$486  (via drill 0.8 pad 1.78)
  other vias: 115.57,86.36
N$487  (via drill 0.8 pad 1.78)
  other vias: 115.57,88.9
N$488  (via drill 0.8 pad 1.78)
  other vias: 115.57,91.44
N$489  (via drill 0.8 pad 1.78)
  other vias: 113.03,91.44
N$490  (via drill 0.8 pad 1.78)
  other vias: 110.49,91.44
N$491  (via drill 0.8 pad 1.78)
  other vias: 110.49,88.9
N$492  (via drill 0.8 pad 1.78)
  other vias: 113.03,88.9
N$493  (via drill 0.8 pad 1.78)
  other vias: 113.03,86.36
N$494  (via drill 0.8 pad 1.78)
  other vias: 110.49,86.36
N$495  (via drill 0.8 pad 1.78)
  other vias: 107.95,86.36
N$496  (via drill 0.8 pad 1.78)
  other vias: 105.41,86.36
N$497  (via drill 0.8 pad 1.78)
  other vias: 102.87,86.36
N$498  (via drill 0.8 pad 1.78)
  other vias: 100.33,86.36
N$499  (via drill 0.8 pad 1.78)
  other vias: 97.79,86.36
N$500  (via drill 0.8 pad 1.78)
  other vias: 95.25,86.36
N$501  (via drill 0.8 pad 1.78)
  other vias: 107.95,88.9
N$502  (via drill 0.8 pad 1.78)
  other vias: 105.41,88.9
N$503  (via drill 0.8 pad 1.78)
  other vias: 102.87,88.9
N$504  (via drill 0.8 pad 1.78)
  other vias: 100.33,88.9
N$505  (via drill 0.8 pad 1.78)
  other vias: 97.79,88.9
N$506  (via drill 0.8 pad 1.78)
  other vias: 97.79,91.44
N$507  (via drill 0.8 pad 1.78)
  other vias: 100.33,91.44
N$508  (via drill 0.8 pad 1.78)
  other vias: 102.87,91.44
N$509  (via drill 0.8 pad 1.78)
  other vias: 105.41,91.44
N$510  (via drill 0.8 pad 1.78)
  other vias: 107.95,91.44
N$511  (via drill 0.8 pad 1.78)
  other vias: 85.09,93.98
N$512  (via drill 0.8 pad 1.78)
  other vias: 85.09,91.44
N$513  (via drill 0.8 pad 1.78)
  other vias: 85.09,88.9
N$514  (via drill 0.8 pad 1.78)
  other vias: 87.63,88.9
N$515  (via drill 0.8 pad 1.78)
  other vias: 87.63,91.44
N$516  (via drill 0.8 pad 1.78)
  other vias: 87.63,93.98
N$517  (via drill 0.8 pad 1.78)
  other vias: 97.79,93.98
N$518  (via drill 0.8 pad 1.78)
  other vias: 95.25,93.98
N$519  (via drill 0.8 pad 1.78)
  other vias: 92.71,93.98
N$520  (via drill 0.8 pad 1.78)
  other vias: 90.17,93.98
N$521  (via drill 0.8 pad 1.78)
  other vias: 90.17,91.44
N$522  (via drill 0.8 pad 1.78)
  other vias: 92.71,91.44
N$523  (via drill 0.8 pad 1.78)
  other vias: 95.25,91.44
N$524  (via drill 0.8 pad 1.78)
  other vias: 95.25,88.9
N$525  (via drill 0.8 pad 1.78)
  other vias: 92.71,88.9
N$526  (via drill 0.8 pad 1.78)
  other vias: 90.17,88.9
N$527  (via drill 0.8 pad 1.78)
  other vias: 100.33,93.98
N$528  (via drill 0.8 pad 1.78)
  other vias: 151.13,93.98
N$529  (via drill 0.8 pad 1.78)
  other vias: 148.59,93.98
N$530  (via drill 0.8 pad 1.78)
  other vias: 146.05,93.98
N$531  (via drill 0.8 pad 1.78)
  other vias: 143.51,93.98
N$532  (via drill 0.8 pad 1.78)
  other vias: 140.97,93.98
N$533  (via drill 0.8 pad 1.78)
  other vias: 138.43,93.98
N$534  (via drill 0.8 pad 1.78)
  other vias: 135.89,93.98
N$535  (via drill 0.8 pad 1.78)
  other vias: 133.35,93.98
N$536  (via drill 0.8 pad 1.78)
  other vias: 130.81,93.98
N$537  (via drill 0.8 pad 1.78)
  other vias: 128.27,93.98
N$538  (via drill 0.8 pad 1.78)
  other vias: 125.73,93.98
N$539  (via drill 0.8 pad 1.78)
  other vias: 123.19,93.98
N$540  (via drill 0.8 pad 1.78)
  other vias: 120.65,93.98
N$541  (via drill 0.8 pad 1.78)
  other vias: 118.11,93.98
N$542  (via drill 0.8 pad 1.78)
  other vias: 115.57,93.98
N$543  (via drill 0.8 pad 1.78)
  other vias: 113.03,93.98
N$544  (via drill 0.8 pad 1.78)
  other vias: 110.49,93.98
N$545  (via drill 0.8 pad 1.78)
  other vias: 107.95,93.98
N$546  (via drill 0.8 pad 1.78)
  other vias: 105.41,93.98
N$547  (via drill 0.8 pad 1.78)
  other vias: 102.87,93.98
N$548  (via drill 0.8 pad 1.78)
  other vias: 59.69,55.88
N$549  (via drill 0.8 pad 1.78)
  other vias: 57.15,55.88
N$550  (via drill 0.8 pad 1.78)
  other vias: 54.61,55.88
N$551  (via drill 0.8 pad 1.78)
  other vias: 52.07,55.88
N$552  (via drill 0.8 pad 1.78)
  other vias: 49.53,55.88
N$553  (via drill 0.8 pad 1.78)
  other vias: 46.99,55.88
N$554  (via drill 0.8 pad 1.78)
  other vias: 44.45,55.88
N$555  (via drill 0.8 pad 1.78)
  other vias: 41.91,55.88
N$556  (via drill 0.8 pad 1.78)
  other vias: 39.37,55.88
N$557  (via drill 0.8 pad 1.78)
  other vias: 36.83,55.88
N$558  (via drill 0.8 pad 1.78)
  other vias: 34.29,55.88
N$559  (via drill 0.8 pad 1.78)
  other vias: 31.75,55.88
N$560  (via drill 0.8 pad 1.78)
  other vias: 29.21,55.88
N$561  (via drill 0.8 pad 1.78)
  other vias: 26.67,55.88
N$562  (via drill 0.8 pad 1.78)
  other vias: 24.13,55.88
N$563  (via drill 0.8 pad 1.78)
  other vias: 21.59,55.88
N$564  (via drill 0.8 pad 1.78)
  other vias: 19.05,55.88
N$565  (via drill 0.8 pad 1.78)
  other vias: 16.51,55.88
N$566  (via drill 0.8 pad 1.78)
  other vias: 13.97,55.88
N$567  (via drill 0.8 pad 1.78)
  other vias: 11.43,55.88
N$568  (via drill 0.8 pad 1.78)
  other vias: 8.89,55.88
N$569  (via drill 0.8 pad 1.78)
  other vias: 6.35,55.88
N$570  (via drill 0.8 pad 1.78)
  other vias: 3.81,55.88
N$571  (via drill 0.8 pad 1.78)
  other vias: 3.81,58.42
N$572  (via drill 0.8 pad 1.78)
  other vias: 36.83,58.42
N$573  (via drill 0.8 pad 1.78)
  other vias: 36.83,60.96
N$574  (via drill 0.8 pad 1.78)
  other vias: 36.83,63.5
N$575  (via drill 0.8 pad 1.78)
  other vias: 36.83,66.04
N$576  (via drill 0.8 pad 1.78)
  other vias: 36.83,68.58
N$577  (via drill 0.8 pad 1.78)
  other vias: 36.83,71.12
N$578  (via drill 0.8 pad 1.78)
  other vias: 34.29,71.12
N$579  (via drill 0.8 pad 1.78)
  other vias: 34.29,68.58
N$580  (via drill 0.8 pad 1.78)
  other vias: 34.29,66.04
N$581  (via drill 0.8 pad 1.78)
  other vias: 34.29,63.5
N$582  (via drill 0.8 pad 1.78)
  other vias: 34.29,60.96
N$583  (via drill 0.8 pad 1.78)
  other vias: 34.29,58.42
N$584  (via drill 0.8 pad 1.78)
  other vias: 39.37,58.42
N$585  (via drill 0.8 pad 1.78)
  other vias: 39.37,60.96
N$586  (via drill 0.8 pad 1.78)
  other vias: 41.91,58.42
N$587  (via drill 0.8 pad 1.78)
  other vias: 44.45,58.42
N$588  (via drill 0.8 pad 1.78)
  other vias: 46.99,58.42
N$589  (via drill 0.8 pad 1.78)
  other vias: 49.53,58.42
N$590  (via drill 0.8 pad 1.78)
  other vias: 52.07,58.42
N$591  (via drill 0.8 pad 1.78)
  other vias: 54.61,58.42
N$592  (via drill 0.8 pad 1.78)
  other vias: 57.15,58.42
N$593  (via drill 0.8 pad 1.78)
  other vias: 59.69,58.42
N$594  (via drill 0.8 pad 1.78)
  other vias: 62.23,58.42
N$595  (via drill 0.8 pad 1.78)
  other vias: 64.77,58.42
N$596  (via drill 0.8 pad 1.78)
  other vias: 64.77,60.96
N$597  (via drill 0.8 pad 1.78)
  other vias: 62.23,60.96
N$598  (via drill 0.8 pad 1.78)
  other vias: 59.69,60.96
N$599  (via drill 0.8 pad 1.78)
  other vias: 57.15,60.96
N$600  (via drill 0.8 pad 1.78)
  other vias: 54.61,60.96
N$601  (via drill 0.8 pad 1.78)
  other vias: 52.07,60.96
N$602  (via drill 0.8 pad 1.78)
  other vias: 49.53,60.96
N$603  (via drill 0.8 pad 1.78)
  other vias: 46.99,60.96
N$604  (via drill 0.8 pad 1.78)
  other vias: 44.45,60.96
N$605  (via drill 0.8 pad 1.78)
  other vias: 41.91,60.96
N$606  (via drill 0.8 pad 1.78)
  other vias: 64.77,63.5
N$607  (via drill 0.8 pad 1.78)
  other vias: 62.23,63.5
N$608  (via drill 0.8 pad 1.78)
  other vias: 59.69,63.5
N$609  (via drill 0.8 pad 1.78)
  other vias: 57.15,63.5
N$610  (via drill 0.8 pad 1.78)
  other vias: 57.15,71.12
N$611  (via drill 0.8 pad 1.78)
  other vias: 57.15,68.58
N$612  (via drill 0.8 pad 1.78)
  other vias: 57.15,66.04
N$613  (via drill 0.8 pad 1.78)
  other vias: 59.69,66.04
N$614  (via drill 0.8 pad 1.78)
  other vias: 59.69,68.58
N$615  (via drill 0.8 pad 1.78)
  other vias: 59.69,71.12
N$616  (via drill 0.8 pad 1.78)
  other vias: 62.23,71.12
N$617  (via drill 0.8 pad 1.78)
  other vias: 62.23,68.58
N$618  (via drill 0.8 pad 1.78)
  other vias: 62.23,66.04
N$619  (via drill 0.8 pad 1.78)
  other vias: 64.77,66.04
N$620  (via drill 0.8 pad 1.78)
  other vias: 64.77,68.58
N$621  (via drill 0.8 pad 1.78)
  other vias: 64.77,71.12
N$622  (via drill 0.8 pad 1.78)
  other vias: 54.61,71.12
N$623  (via drill 0.8 pad 1.78)
  other vias: 54.61,68.58
N$624  (via drill 0.8 pad 1.78)
  other vias: 54.61,66.04
N$625  (via drill 0.8 pad 1.78)
  other vias: 21.59,68.58
N$626  (via drill 0.8 pad 1.78)
  other vias: 54.61,63.5
N$627  (via drill 0.8 pad 1.78)
  other vias: 52.07,63.5
N$628  (via drill 0.8 pad 1.78)
  other vias: 49.53,63.5
N$629  (via drill 0.8 pad 1.78)
  other vias: 46.99,63.5
N$630  (via drill 0.8 pad 1.78)
  other vias: 44.45,63.5
N$631  (via drill 0.8 pad 1.78)
  other vias: 41.91,63.5
N$632  (via drill 0.8 pad 1.78)
  other vias: 39.37,63.5
N$633  (via drill 0.8 pad 1.78)
  other vias: 39.37,66.04
N$634  (via drill 0.8 pad 1.78)
  other vias: 41.91,66.04
N$635  (via drill 0.8 pad 1.78)
  other vias: 44.45,66.04
N$636  (via drill 0.8 pad 1.78)
  other vias: 46.99,66.04
N$637  (via drill 0.8 pad 1.78)
  other vias: 46.99,68.58
N$638  (via drill 0.8 pad 1.78)
  other vias: 46.99,71.12
N$639  (via drill 0.8 pad 1.78)
  other vias: 44.45,71.12
N$640  (via drill 0.8 pad 1.78)
  other vias: 44.45,68.58
N$641  (via drill 0.8 pad 1.78)
  other vias: 41.91,68.58
N$642  (via drill 0.8 pad 1.78)
  other vias: 39.37,68.58
N$643  (via drill 0.8 pad 1.78)
  other vias: 39.37,71.12
N$644  (via drill 0.8 pad 1.78)
  other vias: 41.91,71.12
N$645  (via drill 0.8 pad 1.78)
  other vias: 49.53,71.12
N$646  (via drill 0.8 pad 1.78)
  other vias: 52.07,71.12
N$647  (via drill 0.8 pad 1.78)
  other vias: 52.07,68.58
N$648  (via drill 0.8 pad 1.78)
  other vias: 52.07,66.04
N$649  (via drill 0.8 pad 1.78)
  other vias: 49.53,66.04
N$650  (via drill 0.8 pad 1.78)
  other vias: 49.53,68.58
N$651  (via drill 0.8 pad 1.78)
  other vias: 24.13,58.42
N$652  (via drill 0.8 pad 1.78)
  other vias: 24.13,60.96
N$653  (via drill 0.8 pad 1.78)
  other vias: 24.13,63.5
N$654  (via drill 0.8 pad 1.78)
  other vias: 24.13,66.04
N$655  (via drill 0.8 pad 1.78)
  other vias: 24.13,68.58
N$656  (via drill 0.8 pad 1.78)
  other vias: 24.13,71.12
N$657  (via drill 0.8 pad 1.78)
  other vias: 26.67,71.12
N$658  (via drill 0.8 pad 1.78)
  other vias: 26.67,68.58
N$659  (via drill 0.8 pad 1.78)
  other vias: 26.67,66.04
N$660  (via drill 0.8 pad 1.78)
  other vias: 26.67,63.5
N$661  (via drill 0.8 pad 1.78)
  other vias: 26.67,60.96
N$662  (via drill 0.8 pad 1.78)
  other vias: 26.67,58.42
N$663  (via drill 0.8 pad 1.78)
  other vias: 29.21,58.42
N$664  (via drill 0.8 pad 1.78)
  other vias: 31.75,58.42
N$665  (via drill 0.8 pad 1.78)
  other vias: 31.75,60.96
N$666  (via drill 0.8 pad 1.78)
  other vias: 29.21,60.96
N$667  (via drill 0.8 pad 1.78)
  other vias: 29.21,63.5
N$668  (via drill 0.8 pad 1.78)
  other vias: 31.75,66.04
N$669  (via drill 0.8 pad 1.78)
  other vias: 31.75,63.5
N$670  (via drill 0.8 pad 1.78)
  other vias: 31.75,68.58
N$671  (via drill 0.8 pad 1.78)
  other vias: 29.21,68.58
N$672  (via drill 0.8 pad 1.78)
  other vias: 29.21,66.04
N$673  (via drill 0.8 pad 1.78)
  other vias: 29.21,71.12
N$674  (via drill 0.8 pad 1.78)
  other vias: 31.75,71.12
N$675  (via drill 0.8 pad 1.78)
  other vias: 59.69,78.74
N$676  (via drill 0.8 pad 1.78)
  other vias: 62.23,78.74
N$677  (via drill 0.8 pad 1.78)
  other vias: 64.77,78.74
N$678  (via drill 0.8 pad 1.78)
  other vias: 24.13,78.74
N$679  (via drill 0.8 pad 1.78)
  other vias: 26.67,78.74
N$680
  Bottom 0.813: 39.37,55.88 39.37,71.12
N$681  (via drill 0.8 pad 1.78)
  other vias: 31.75,78.74
N$682  (via drill 0.8 pad 1.78)
  other vias: 34.29,78.74
N$683  (via drill 0.8 pad 1.78)
  other vias: 36.83,78.74
N$684  (via drill 0.8 pad 1.78)
  other vias: 39.37,78.74
N$685  (via drill 0.8 pad 1.78)
  other vias: 41.91,78.74
N$686  (via drill 0.8 pad 1.78)
  other vias: 44.45,78.74
N$687  (via drill 0.8 pad 1.78)
  other vias: 57.15,78.74
N$688  (via drill 0.8 pad 1.78)
  other vias: 54.61,78.74
N$689  (via drill 0.8 pad 1.78)
  other vias: 52.07,78.74
N$690  (via drill 0.8 pad 1.78)
  other vias: 49.53,78.74
N$691  (via drill 0.8 pad 1.78)
  other vias: 46.99,78.74
N$692  (via drill 0.8 pad 1.78)
  other vias: 46.99,81.28
N$693  (via drill 0.8 pad 1.78)
  other vias: 44.45,81.28
N$694  (via drill 0.8 pad 1.78)
  other vias: 41.91,81.28
N$695  (via drill 0.8 pad 1.78)
  other vias: 39.37,81.28
N$696  (via drill 0.8 pad 1.78)
  other vias: 36.83,81.28
N$697  (via drill 0.8 pad 1.78)
  other vias: 34.29,81.28
N$698  (via drill 0.8 pad 1.78)
  other vias: 31.75,81.28
N$699  (via drill 0.8 pad 1.78)
  other vias: 29.21,81.28
N$700  (via drill 0.8 pad 1.78)
  other vias: 26.67,81.28
N$701  (via drill 0.8 pad 1.78)
  other vias: 24.13,81.28
N$702  (via drill 0.8 pad 1.78)
  other vias: 36.83,83.82
N$703  (via drill 0.8 pad 1.78)
  other vias: 36.83,86.36
N$704  (via drill 0.8 pad 1.78)
  other vias: 36.83,93.98
N$705  (via drill 0.8 pad 1.78)
  other vias: 36.83,91.44
N$706  (via drill 0.8 pad 1.78)
  other vias: 36.83,88.9
N$707  (via drill 0.8 pad 1.78)
  other vias: 46.99,83.82
N$708  (via drill 0.8 pad 1.78)
  other vias: 46.99,86.36
N$709  (via drill 0.8 pad 1.78)
  other vias: 44.45,86.36
N$710  (via drill 0.8 pad 1.78)
  other vias: 41.91,86.36
N$711  (via drill 0.8 pad 1.78)
  other vias: 39.37,86.36
N$712  (via drill 0.8 pad 1.78)
  other vias: 39.37,83.82
N$713  (via drill 0.8 pad 1.78)
  other vias: 41.91,83.82
N$714  (via drill 0.8 pad 1.78)
  other vias: 44.45,83.82
N$715  (via drill 0.8 pad 1.78)
  other vias: 57.15,93.98
N$716  (via drill 0.8 pad 1.78)
  other vias: 57.15,91.44
N$717  (via drill 0.8 pad 1.78)
  other vias: 57.15,88.9
N$718  (via drill 0.8 pad 1.78)
  other vias: 62.23,83.82
N$719  (via drill 0.8 pad 1.78)
  other vias: 49.53,86.36
N$720  (via drill 0.8 pad 1.78)
  other vias: 49.53,83.82
N$721  (via drill 0.8 pad 1.78)
  other vias: 49.53,81.28
N$722  (via drill 0.8 pad 1.78)
  other vias: 52.07,81.28
N$723  (via drill 0.8 pad 1.78)
  other vias: 54.61,81.28
N$724  (via drill 0.8 pad 1.78)
  other vias: 57.15,81.28
N$725  (via drill 0.8 pad 1.78)
  other vias: 59.69,81.28
N$726  (via drill 0.8 pad 1.78)
  other vias: 62.23,81.28
N$727  (via drill 0.8 pad 1.78)
  other vias: 64.77,81.28
N$728  (via drill 0.8 pad 1.78)
  other vias: 59.69,83.82
N$729  (via drill 0.8 pad 1.78)
  other vias: 59.69,86.36
N$730  (via drill 0.8 pad 1.78)
  other vias: 57.15,86.36
N$731  (via drill 0.8 pad 1.78)
  other vias: 57.15,83.82
N$732  (via drill 0.8 pad 1.78)
  other vias: 54.61,83.82
N$733  (via drill 0.8 pad 1.78)
  other vias: 52.07,83.82
N$734  (via drill 0.8 pad 1.78)
  other vias: 54.61,88.9
N$735  (via drill 0.8 pad 1.78)
  other vias: 52.07,86.36
N$736  (via drill 0.8 pad 1.78)
  other vias: 54.61,86.36
N$737  (via drill 0.8 pad 1.78)
  other vias: 52.07,88.9
N$738  (via drill 0.8 pad 1.78)
  other vias: 54.61,91.44
N$739  (via drill 0.8 pad 1.78)
  other vias: 52.07,91.44
N$740  (via drill 0.8 pad 1.78)
  other vias: 52.07,93.98
N$741  (via drill 0.8 pad 1.78)
  other vias: 54.61,93.98
N$742  (via drill 0.8 pad 1.78)
  other vias: 64.77,83.82
N$743  (via drill 0.8 pad 1.78)
  other vias: 64.77,86.36
N$744  (via drill 0.8 pad 1.78)
  other vias: 62.23,86.36
N$745  (via drill 0.8 pad 1.78)
  other vias: 64.77,93.98
N$746  (via drill 0.8 pad 1.78)
  other vias: 62.23,93.98
N$747  (via drill 0.8 pad 1.78)
  other vias: 59.69,93.98
N$748  (via drill 0.8 pad 1.78)
  other vias: 59.69,91.44
N$749  (via drill 0.8 pad 1.78)
  other vias: 62.23,91.44
N$750  (via drill 0.8 pad 1.78)
  other vias: 64.77,91.44
N$751  (via drill 0.8 pad 1.78)
  other vias: 64.77,88.9
N$752  (via drill 0.8 pad 1.78)
  other vias: 62.23,88.9
N$753  (via drill 0.8 pad 1.78)
  other vias: 59.69,88.9
N$754  (via drill 0.8 pad 1.78)
  other vias: 49.53,88.9
N$755  (via drill 0.8 pad 1.78)
  other vias: 49.53,91.44
N$756  (via drill 0.8 pad 1.78)
  other vias: 49.53,93.98
N$757  (via drill 0.8 pad 1.78)
  other vias: 46.99,93.98
N$758  (via drill 0.8 pad 1.78)
  other vias: 46.99,91.44
N$759  (via drill 0.8 pad 1.78)
  other vias: 46.99,88.9
N$760  (via drill 0.8 pad 1.78)
  other vias: 44.45,88.9
N$761  (via drill 0.8 pad 1.78)
  other vias: 41.91,88.9
N$762  (via drill 0.8 pad 1.78)
  other vias: 39.37,88.9
N$763  (via drill 0.8 pad 1.78)
  other vias: 39.37,91.44
N$764  (via drill 0.8 pad 1.78)
  other vias: 39.37,93.98
N$765  (via drill 0.8 pad 1.78)
  other vias: 41.91,93.98
N$766  (via drill 0.8 pad 1.78)
  other vias: 44.45,93.98
N$767  (via drill 0.8 pad 1.78)
  other vias: 44.45,91.44
N$768  (via drill 0.8 pad 1.78)
  other vias: 41.91,91.44
N$769  (via drill 0.8 pad 1.78)
  other vias: 21.59,78.74
N$770  (via drill 0.8 pad 1.78)
  other vias: 19.05,78.74
N$771  (via drill 0.8 pad 1.78)
  other vias: 16.51,78.74
N$772  (via drill 0.8 pad 1.78)
  other vias: 13.97,78.74
N$773  (via drill 0.8 pad 1.78)
  other vias: 11.43,78.74
N$774  (via drill 0.8 pad 1.78)
  other vias: 8.89,78.74
N$775  (via drill 0.8 pad 1.78)
  other vias: 6.35,78.74
N$776  (via drill 0.8 pad 1.78)
  other vias: 21.59,71.12
N$777  (via drill 0.8 pad 1.78)
  other vias: 19.05,71.12
N$778  (via drill 0.8 pad 1.78)
  other vias: 16.51,71.12
N$779  (via drill 0.8 pad 1.78)
  other vias: 13.97,71.12
N$780  (via drill 0.8 pad 1.78)
  other vias: 11.43,71.12
N$781  (via drill 0.8 pad 1.78)
  other vias: 8.89,71.12
N$782  (via drill 0.8 pad 1.78)
  other vias: 6.35,71.12
N$783  (via drill 0.8 pad 1.78)
  other vias: 6.35,81.28
N$784  (via drill 0.8 pad 1.78)
  other vias: 6.35,83.82
N$785  (via drill 0.8 pad 1.78)
  other vias: 6.35,86.36
N$786  (via drill 0.8 pad 1.78)
  other vias: 6.35,88.9
N$787  (via drill 0.8 pad 1.78)
  other vias: 6.35,91.44
N$788  (via drill 0.8 pad 1.78)
  other vias: 6.35,93.98
N$789
  Bottom 0.813: 140.97,78.74 140.97,93.98
N$790  (via drill 0.8 pad 1.78)
  other vias: 8.89,93.98
N$791  (via drill 0.8 pad 1.78)
  other vias: 8.89,91.44
N$792  (via drill 0.8 pad 1.78)
  other vias: 8.89,88.9
N$793  (via drill 0.8 pad 1.78)
  other vias: 8.89,86.36
N$794  (via drill 0.8 pad 1.78)
  other vias: 8.89,83.82
N$795  (via drill 0.8 pad 1.78)
  other vias: 8.89,81.28
N$796  (via drill 0.8 pad 1.78)
  other vias: 11.43,81.28
N$797  (via drill 0.8 pad 1.78)
  other vias: 13.97,81.28
N$798  (via drill 0.8 pad 1.78)
  other vias: 16.51,81.28
N$799  (via drill 0.8 pad 1.78)
  other vias: 16.51,83.82
N$800  (via drill 0.8 pad 1.78)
